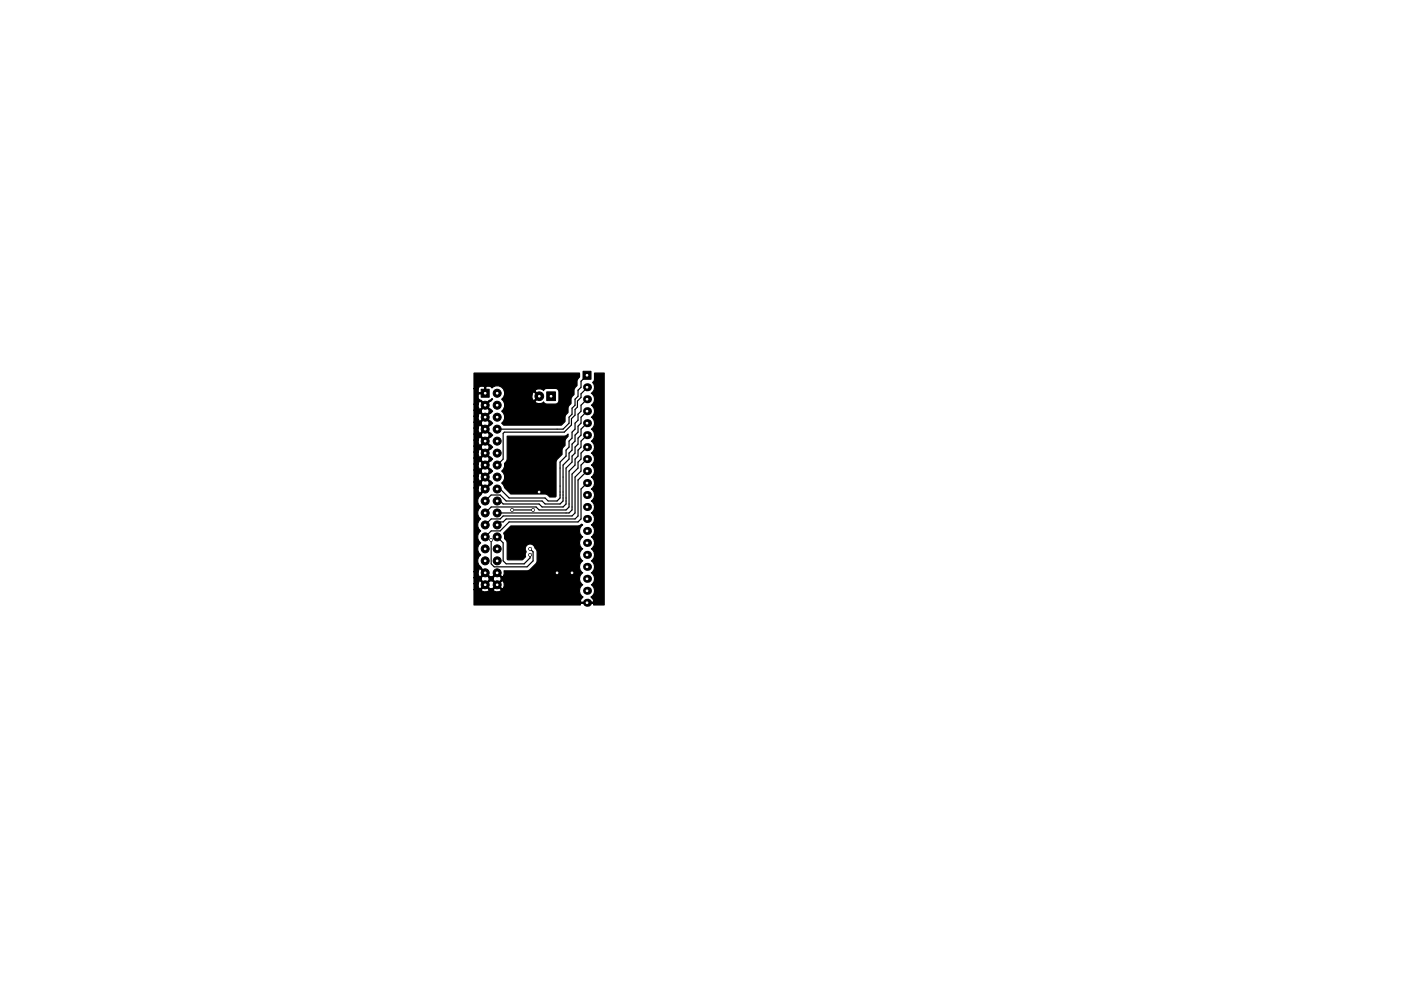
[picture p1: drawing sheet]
<svg xmlns="http://www.w3.org/2000/svg" width="297mm" height="210mm" viewBox="0 0 297 210" stroke-linecap="round" stroke-linejoin="round" font-family="sans-serif">
<g fill="#000" stroke="#000" stroke-width=".21">
<path d="M102 82.6h1.7v1.7h-1.7zM115.9 83.1h1.9v1.9h-1.9zM123.6 78.8h1.7v1.7h-1.7z"/>
<circle cx="102.9" cy="88.5" r=".85"/>
<circle cx="102.9" cy="86" r=".85"/>
<circle cx="102.9" cy="93.6" r=".85"/>
<circle cx="102.9" cy="96.1" r=".85"/>
<circle cx="102.9" cy="91.1" r=".85"/>
<circle cx="102.9" cy="98.7" r=".85"/>
<circle cx="105.4" cy="88.5" r=".85"/>
<circle cx="105.4" cy="83.4" r=".85"/>
<circle cx="105.4" cy="96.1" r=".85"/>
<circle cx="105.4" cy="86" r=".85"/>
<circle cx="105.4" cy="93.6" r=".85"/>
<circle cx="105.4" cy="98.7" r=".85"/>
<circle cx="105.4" cy="91.1" r=".85"/>
<circle cx="114.3" cy="84.1" r=".92"/>
<circle cx="102.9" cy="101.2" r=".85"/>
<circle cx="102.9" cy="111.4" r=".85"/>
<circle cx="102.9" cy="119" r=".85"/>
<circle cx="102.9" cy="113.9" r=".85"/>
<circle cx="102.9" cy="103.8" r=".85"/>
<circle cx="102.9" cy="106.3" r=".85"/>
<circle cx="102.9" cy="116.5" r=".85"/>
<circle cx="102.9" cy="108.8" r=".85"/>
<circle cx="104.1" cy="114.5" r=".3"/>
<circle cx="105.4" cy="113.9" r=".85"/>
<circle cx="105.4" cy="101.2" r=".85"/>
<circle cx="105.4" cy="111.4" r=".85"/>
<circle cx="105.4" cy="116.5" r=".85"/>
<circle cx="105.4" cy="119" r=".85"/>
<circle cx="105.4" cy="103.8" r=".85"/>
<circle cx="105.4" cy="106.3" r=".85"/>
<circle cx="105.4" cy="108.8" r=".85"/>
<circle cx="108.6" cy="108.2" r=".3"/>
<circle cx="112.4" cy="116.5" r=".3"/>
<circle cx="112.4" cy="117.7" r=".3"/>
<circle cx="113" cy="108.2" r=".3"/>
<circle cx="114.3" cy="104.4" r=".3"/>
<circle cx="102.9" cy="121.5" r=".85"/>
<circle cx="102.9" cy="124.1" r=".85"/>
<circle cx="105.4" cy="121.5" r=".85"/>
<circle cx="105.4" cy="124.1" r=".85"/>
<circle cx="118.1" cy="121.5" r=".3"/>
<circle cx="121.3" cy="121.5" r=".3"/>
</g>
<g fill="#000">
<circle cx="124.5" cy="92.3" r=".85"/>
<circle cx="124.5" cy="84.7" r=".85"/>
<circle cx="124.5" cy="94.9" r=".85"/>
<circle cx="124.5" cy="82.2" r=".85"/>
<circle cx="124.5" cy="87.2" r=".85"/>
<circle cx="124.5" cy="97.4" r=".85"/>
<circle cx="124.5" cy="89.8" r=".85"/>
<circle cx="124.5" cy="99.9" r=".85"/>
<circle cx="124.5" cy="110.1" r=".85"/>
<circle cx="124.5" cy="112.6" r=".85"/>
<circle cx="124.5" cy="107.6" r=".85"/>
<circle cx="124.5" cy="115.2" r=".85"/>
<circle cx="124.5" cy="117.7" r=".85"/>
<circle cx="124.5" cy="102.5" r=".85"/>
<circle cx="124.5" cy="105" r=".85"/>
<circle cx="124.5" cy="122.8" r=".85"/>
<circle cx="124.5" cy="127.9" r=".85"/>
<circle cx="124.5" cy="120.3" r=".85"/>
<circle cx="124.5" cy="125.3" r=".85"/>
</g>
<path d="M118.1 121.5h3.2" fill="none" stroke="#000" stroke-width=".5"/>
<g fill="none" stroke="#000" stroke-width=".25">
<path d="M124.5 79.6l-1.3 1.3v1.3l-.6 .6v1.3l-.7 .6v1.3l-.6 .6v1.3l-.7 .6v1.3l-1.2 1.3h-14M124.5 82.2l-1.3 1.4v.7l-.8 .8v1.3l-.5 .5v1.2l-.7 .7v1.4l-1.6 1.5h-12.7l-.2 .2v5.5l-1.3 1.3M124.5 84.7l-1.3 1.3v1.2l-.6 .7v1.2l-.7 .7v1.3l-.6 .6v1.3l-.7 .6v1.3l-.6 .6v1.3l-1.3 1.2v7.7l-.6 .6h-1.9l-.6-.6h-7.7l-1.9-1.9h-.6M124.5 87.2l-1.3 1.3v1.3l-.6 .6v1.3l-.7 .6v1.3l-.6 .6v1.3l-.7 .6v1.3l-1.2 1.3v7.6l-.7 .6h-3.1l-.7-.6h-7.6l-1.3-1.3h-1.9l-1.2 1.3M124.5 89.8l-1.3 1.3v1.2l-.6 .7v1.2l-.7 .7v1.2l-.6 .7v1.2l-1.3 1.3v7.6l-.6 .7h-4.5l-.6-.7h-7.6l-.7-.6h-.6M124.5 92.3l-1.3 1.3v1.3l-.6 .6v1.3l-.7 .6v1.3l-1.3 1.2v7.7l-.6 .6h-5.7l-.6-.6h-9.6l-1.2 1.2M124.5 94.9l-1.3 1.2v1.3l-.6 .6v1.3l-1.3 1.3v7.6l-.7 .6h-15.2M124.5 97.4l-1.3 1.3v1.2l-1.3 1.3v7.6l-.6 .7h-14.6l-.7 .6h-1.9l-1.2 1.3M124.5 99.9l-1.9 1.9v7.7l-.7 .6h-14.6l-.6 .6h-.7l-.6 .7M104.1 114.5v5.1l.7 .7h7l1.2-1.3v-1.9l-.6-.6M105.4 113.9l1.3 1.3v3.8l.6 .6h3.8l1.3-1.2v-.7M108.6 108.2h4.4"/>
<path d="M124.5 102.5l-1.3 1.3v6.3l-.6 .6h-14.7l-1.9 1.9h-1.9l-1.2 1.3"/>
</g>
<path d="M107.5 92.5h12.1l.8-.4v.5a1.64 1.64 0 0 0-.6 1.9 1.64 1.64 0 0 0-.6 1.9l-1.1 1-.2 .6v7.3l-.1 .1h-1.2l-.7-.5-.3-.1h-7.3l-1.3-1.3-.3-.6-.3-.4a1.57 1.57 0 0 0 0-2.6 1.54 1.54 0 0 0 .6-1.6l.5-.6v-.3zM100.5 79.2h22.4v.8l-.5 .6-.1 1.2a1.64 1.64 0 0 0-.6 1.9 1.64 1.64 0 0 0-.6 1.9 1.64 1.64 0 0 0-.7 1.9 1.64 1.64 0 0 0-.6 1.9l-.8 .8h-12.2l-.4-.4a1.57 1.57 0 0 0 0-2.6 1.57 1.57 0 0 0 0-2.5l.6-.9h5.8v.6l.2 .5 .2 .1 1-.9-1-1-.2 .1-.2 .6h-5.8l-.1-.8h6.5l1.1 1.1-1.1 1.1 .1 .2a1.25 1.25 0 0 0 1.7-.1l.2 .2 .5 .2h1.9a.74 .74 0 0 0 .7-.7v-1.9l-.2-.5-.2-.1-2.2-.1-.5 .2-.2 .3a1.13 1.13 0 0 0-1.8 .1h-6.5l-.2-.5a1.57 1.57 0 0 0-2.4-.2l-.5-.4h-.6l-.2 .2v1.5h-1.5l-.1 .1 .1 .9 .5 .3 .9 .9 .8-.9 .4-.1 .2-.2 .1 .1-1.4 1.3 1.4 1.2-1.4 1.3 1.4 1.3-1.4 1.3 1.4 1.2-1.4 1.3 1.4 1.3-1.4 1.2 1.4 1.3-1.4 1.3 1.4 1.2-1.4 1.3 1.4 1.3-2.4 2.5a1.59 1.59 0 0 0-.1 2.6 1.57 1.57 0 0 0 0 2.5 1.57 1.57 0 0 0 0 2.5 1.57 1.57 0 0 0 0 2.6 1.57 1.57 0 0 0 0 2.5 1.57 1.57 0 0 0 .1 2.7v.1l1.9 1.9h.5l1-1.1 1.1 1.1a1.05 1.05 0 0 0 .4-1.3h4.9l.6-.2 1.4-1.6 .1-2.2-.5-.8a1.07 1.07 0 0 0-1.5-.8 1.07 1.07 0 0 0-.4 1.6l-.1 .4v.6l-.6 .7h-3.1l-.2-.2v-3.4v-.3l-.5-.6v-.7l-.2-.5 1.5-1.5h14.3l.7-.4 .2 .2a1.51 1.51 0 0 0 0 2.5 1.51 1.51 0 0 0 0 2.6 1.51 1.51 0 0 0 0 2.5 1.51 1.51 0 0 0 0 2.5 1.51 1.51 0 0 0 0 2.6 1.51 1.51 0 0 0 .1 2.6l-.4 .4-.2 .4 .1 .3h2.7l.1-.3-.2-.4-.4-.4 .3-.2a1.54 1.54 0 0 0-.2-2.4 1.51 1.51 0 0 0 0-2.6 1.51 1.51 0 0 0 0-2.5 1.51 1.51 0 0 0 0-2.5 1.51 1.51 0 0 0 0-2.6 1.51 1.51 0 0 0 0-2.5 1.51 1.51 0 0 0 0-2.6 1.51 1.51 0 0 0 0-2.5 1.51 1.51 0 0 0 0-2.5 1.51 1.51 0 0 0 0-2.6 1.51 1.51 0 0 0 0-2.5 1.51 1.51 0 0 0 0-2.6 1.51 1.51 0 0 0 0-2.5 1.51 1.51 0 0 0 0-2.5 1.51 1.51 0 0 0 0-2.6 1.51 1.51 0 0 0 0-2.5 1.51 1.51 0 0 0 0-2.6 1.5 1.5 0 0 0 .3-2.3l.3-.3 .1-1.6h2v49.2h-2.2l-.1-.4h-2.7v.4h-22.6v-3.3h1.5l.1 .3a1.1 1.1 0 0 0 1.6-.3h.8l.1 .3a1.1 1.1 0 0 0 1.7-.3l-.9-.8-.9 .8h-.8l-.8-.8-.9 .8h-1.5v-1.3h.9v.6l.2 .5h.2l.9-.8h.3l.9 .8h.5l.8-.8h.4l.9 .8h.2a1.1 1.1 0 0 0-.2-1.7l-.9 .9h-.4l-.8-.9h-.5l-.9 .9h-.3l-.9-.9-.2 .1-.2 .5h-.9v-1.2h1.5v.4l.9 .9 .8-.9v-.4h.8v.4l.9 .9 .9-.9v-.4l-.9-.9-.9 .9h-.8l-.8-.9-.9 .9h-1.5v-1.3h.9v.6l.2 .4 .2 .1 .9-.9-.9-.8h-.2l-.2 .6h-.9v-17.8h.9v.6l.2 .4 .2 .1 .9-.8-.9-.9-.2 .1-.2 .5h-.9v-1.2h1.5v.4l.9 .9 .8-.9v-.4l-.8-.9-.9 .9h-1.5v-1.3h.9v.6l.2 .4 .2 .1 .9-.9-.9-.9-.2 .1-.2 .6h-.9v-1.3h1.5v.5l.9 .8 .8-.8v-.5l-.8-.8-.9 .8h-1.5v-1.3h.9v.6l.2 .5h.2l.9-.8-.9-.9-.2 .1-.2 .5h-.9v-1.2h1.5v.4l.9 .9 .8-.9v-.4l-.8-.9-.9 .9h-1.5v-1.3h.9v.6l.2 .4 .2 .1 .9-.9-.9-.8h-.2l-.2 .6h-.9v-1.3h1.5v.5l.9 .9 .8-.9v-.5l-.8-.8-.9 .8h-1.5v-1.2h.9v.6l.2 .4 .2 .1 .9-.9-.9-.9-.2 .1-.2 .6h-.9v-1.3h1.5v.4l.9 .9 .8-.9v-.4l-.8-.9-.9 .9h-1.5v-1.3h.9v.6l.2 .4 .2 .1 .9-.8-.9-.9-.2 .1-.2 .5h-.9v-1.2h1.5v.4l.9 .9 .8-.9v-.4l-.8-.9-.9 .9h-1.5v-1.3h.9v.6l.2 .4 .2 .1 .9-.9-.9-.9-.2 .1-.2 .6h-.9v-1.3h1.5v.5l.9 .8 .8-.8v-.5l-.8-.8-.9 .8h-1.5v-1.3h.9v.6l.2 .5h.2l.9-.8-.9-.9-.2 .1-.2 .5h-.9v-3.2h.9v.6l.1 .2h1.2v-1.2l-.1-.2-.9 .1-.3 .5h-.9z" fill="#000" stroke="#000" stroke-width=".25"/>
<g fill="#fff" stroke="#fff" stroke-width=".21">
<circle cx="118.1" cy="121.5" r=".17"/>
<circle cx="121.3" cy="121.5" r=".17"/>
<circle cx="114.3" cy="104.4" r=".17"/>
<circle cx="104.1" cy="114.5" r=".17"/>
<circle cx="112.4" cy="116.5" r=".17"/>
<circle cx="113" cy="108.2" r=".17"/>
<circle cx="108.6" cy="108.2" r=".17"/>
<circle cx="112.4" cy="117.7" r=".17"/>
<circle cx="124.5" cy="79.6" r=".17"/>
<circle cx="124.5" cy="82.2" r=".17"/>
<circle cx="124.5" cy="84.7" r=".17"/>
<circle cx="124.5" cy="87.2" r=".17"/>
<circle cx="124.5" cy="89.8" r=".17"/>
<circle cx="124.5" cy="92.3" r=".17"/>
<circle cx="124.5" cy="94.9" r=".17"/>
<circle cx="124.5" cy="97.4" r=".17"/>
<circle cx="124.5" cy="99.9" r=".17"/>
<circle cx="124.5" cy="102.5" r=".17"/>
<circle cx="124.5" cy="105" r=".17"/>
<circle cx="124.5" cy="107.6" r=".17"/>
<circle cx="124.5" cy="110.1" r=".17"/>
<circle cx="124.5" cy="112.6" r=".17"/>
<circle cx="124.5" cy="115.2" r=".17"/>
<circle cx="124.5" cy="117.7" r=".17"/>
<circle cx="124.5" cy="120.3" r=".17"/>
<circle cx="124.5" cy="122.8" r=".17"/>
<circle cx="124.5" cy="125.3" r=".17"/>
<circle cx="124.5" cy="127.9" r=".17"/>
<circle cx="102.9" cy="83.4" r=".17"/>
<circle cx="105.4" cy="83.4" r=".17"/>
<circle cx="102.9" cy="86" r=".17"/>
<circle cx="105.4" cy="86" r=".17"/>
<circle cx="102.9" cy="88.5" r=".17"/>
<circle cx="105.4" cy="88.5" r=".17"/>
<circle cx="102.9" cy="91.1" r=".17"/>
<circle cx="105.4" cy="91.1" r=".17"/>
<circle cx="102.9" cy="93.6" r=".17"/>
<circle cx="105.4" cy="93.6" r=".17"/>
<circle cx="102.9" cy="96.1" r=".17"/>
<circle cx="105.4" cy="96.1" r=".17"/>
<circle cx="102.9" cy="98.7" r=".17"/>
<circle cx="105.4" cy="98.7" r=".17"/>
<circle cx="102.9" cy="101.2" r=".17"/>
<circle cx="105.4" cy="101.2" r=".17"/>
<circle cx="102.9" cy="103.8" r=".17"/>
<circle cx="105.4" cy="103.8" r=".17"/>
<circle cx="102.9" cy="106.3" r=".17"/>
<circle cx="105.4" cy="106.3" r=".17"/>
<circle cx="102.9" cy="108.8" r=".17"/>
<circle cx="105.4" cy="108.8" r=".17"/>
<circle cx="102.9" cy="111.4" r=".17"/>
<circle cx="105.4" cy="111.4" r=".17"/>
<circle cx="102.9" cy="113.9" r=".17"/>
<circle cx="105.4" cy="113.9" r=".17"/>
<circle cx="102.9" cy="116.5" r=".17"/>
<circle cx="105.4" cy="116.5" r=".17"/>
<circle cx="102.9" cy="119" r=".17"/>
<circle cx="105.4" cy="119" r=".17"/>
<circle cx="102.9" cy="121.5" r=".17"/>
<circle cx="105.4" cy="121.5" r=".17"/>
<circle cx="102.9" cy="124.1" r=".17"/>
<circle cx="105.4" cy="124.1" r=".17"/>
<circle cx="116.8" cy="84.1" r=".17"/>
<circle cx="114.3" cy="84.1" r=".17"/>
</g>
</svg>
